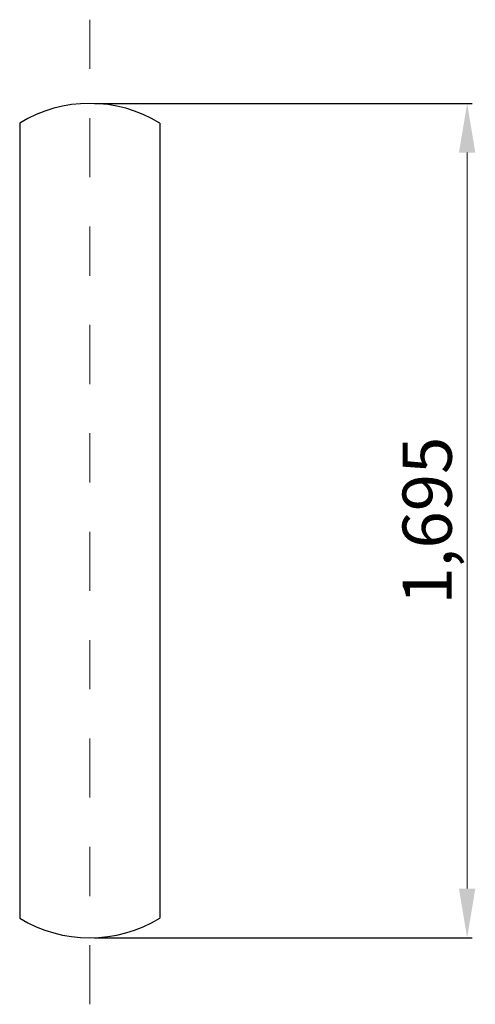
# Model space of a CAD drawing. Units: inches. Extents: x 1.86 to 2.78, y -0.2 to 1.8.
import ezdxf

# ---------------------------------------------------------------- set-up
doc = ezdxf.new("R2010")
doc.units = ezdxf.units.IN
doc.header["$LTSCALE"] = 0.01
doc.linetypes.add('ACAD_ISO10W100', pattern=[18, 12, -3, 0, -3])
doc.dimstyles.new('ISO-25', dxfattribs={"dimtxt": 0.1, "dimasz": 0.1, "dimexe": 0.01, "dimexo": 0.01, "dimgap": 0.01, "dimtad": 1, "dimdec": 4, "dimtxsty": 'Standard', "dimcen": 0.1, "dimadec": 0, "dimazin": 0, "dimtfac": 1, "dimtdec": 4, "dimtmove": 0, "dimatfit": 3, "dimfxl": 0, "dimlwd": 13, "dimarcsym": 0})

# ---------------------------------------------------------------- blocks, each defined once
blk = doc.blocks.new('*D7')
at = {"color": 0, "lineweight": -2, "ltscale": 0.13}
for p, q in [((2.01, 1.63), (2.7775, 1.63)), ((2.01, -0.065), (2.7775, -0.065))]:
    blk.add_line(p, q, dxfattribs=at)
at = {"color": 0, "lineweight": 13, "ltscale": 0.13}
blk.add_line((2.7675, 1.53), (2.7675, 0.035), dxfattribs=at)
for points in [[(2.7508, 1.53), (2.7841, 1.53), (2.7675, 1.63)], [(2.7508, 0.035), (2.7841, 0.035), (2.7675, -0.065)]]:
    blk.add_solid(points, dxfattribs=at)
at = {"layer": 'Defpoints', "color": 0, "lineweight": 13, "ltscale": 0.13}
for p in [(2, 1.63), (2, -0.065), (2.7675, -0.065)]:
    blk.add_point(p, dxfattribs=at)
at = {"color": 0, "lineweight": 13, "ltscale": 0.13, "insert": (2.6991, 0.7825), "char_height": 0.1, "attachment_point": 5, "rotation": 90}
blk.add_mtext('1,695', dxfattribs=at)

msp = doc.modelspace()

# ---------------------------------------------------------------- linework, layer by layer
at = {"color": 1, "linetype": 'ACAD_ISO10W100', "lineweight": 13}
msp.add_line((2, -0.2), (2, 1.8), dxfattribs=at)
at = {"lineweight": 25, "ltscale": 0.13}
for p, q in [((1.8575, 1.59), (1.8575, -0.025)), ((2.1425, 1.59), (2.1425, -0.025))]:
    msp.add_line(p, q, dxfattribs=at)
for centre, start, end in [((2, 1.35617), 58.64097, 121.35903), ((2, 0.20883), 238.64097, 301.35903)]:
    msp.add_arc(centre, 0.27383, start, end, dxfattribs=at)

# ---------------------------------------------------------------- dimensions: what is measured, and where the dimension line sits
at = {"color": 3, "lineweight": 13, "ltscale": 0.13}
dim = msp.add_linear_dim(base=(2.76745, -0.065), p1=(2, 1.63), p2=(2, -0.065), angle=90, dimstyle='ISO-25', dxfattribs=at)
dim.commit()
dim.dimension.update_dxf_attribs({"geometry": '*D7', "text_midpoint": (2.69912, 0.7825)})

doc.saveas('drawing.dxf')
